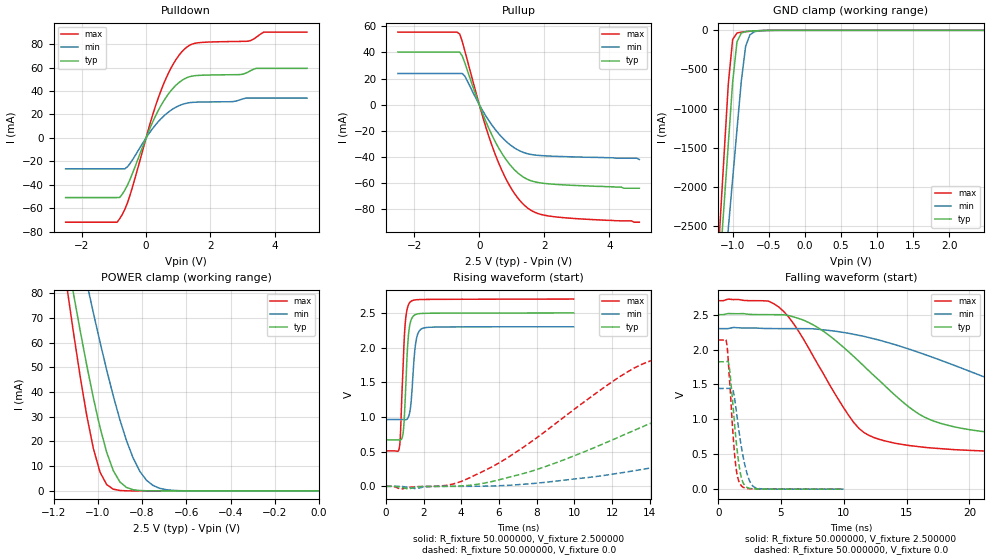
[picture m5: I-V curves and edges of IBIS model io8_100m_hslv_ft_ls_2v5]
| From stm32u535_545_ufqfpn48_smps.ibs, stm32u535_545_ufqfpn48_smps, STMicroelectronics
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|   Model io8_100m_hslv_ft_ls_2v5
[Model]  io8_100m_hslv_ft_ls_2v5
Model_type I/O
Polarity   Non-Inverting
Enable   Active-Low
Vinl =   0.750000V
Vinh =   1.750000V
Vmeas =  1.250000V
Cref =   50.000000pF
Rref =   100.000000M
Vref =   0.0V
C_comp   3.340800pF   3.338500pF   3.380300pF
[Temperature Range]   25.000000   0.140000k   -40.000000
[Pullup Reference]   2.500000V   2.300000V   2.700000V
[Pulldown Reference]   0.0V   0.0V   0.0V
[POWER Clamp Reference]   2.500000V   2.300000V   2.700000V
[GND Clamp Reference]   0.0V   0.0V   0.0V
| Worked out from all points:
|   slope of the pulldown table from 0 to 0.375 V, typ, clamps not added: 16.1 ohm
|   slope of the pullup table from 0 to 0.375 V, typ, clamps not added: 16.6 ohm
|   GND clamp passes 1 mA (typ) near -0.50 V on its own axis
|   POWER clamp passes 1 mA (typ) near -0.86 V on its own axis
|   rising waveform, R_fixture 50.000000, V_fixture 2.500000: 20-80 % time 198ps typ, 224ps min, 202ps max; typ from 0.67 V to 2.5 V
|   rising waveform, R_fixture 50.000000, V_fixture 0.0: 20-80 % time 9.99ns typ, 18.1ns min, 6.67ns max; typ from 0 V to 1.82 V
|   falling waveform, R_fixture 50.000000, V_fixture 2.500000: 20-80 % time 7.07ns typ, 14.1ns min, 4.42ns max; typ from 2.5 V to 0.67 V
|   falling waveform, R_fixture 50.000000, V_fixture 0.0: 20-80 % time 599ps typ, 783ps min, 496ps max; typ from 1.82 V to 0 V
[Pulldown]
|Voltage   I(typ)   I(min)   I(max)
-2.5V     -51mA      -26.45mA   -72.04mA
-900mV    -51mA      -26.45mA   -72.04mA
-820mV    -50.89mA   -26.45mA   -69.09mA
-500mV    -35.59mA   -21.93mA   -49.09mA
140mV     9.489mA    5.639mA    13.76mA
460mV     27.5mA     16.24mA    40.22mA
860mV     43.07mA    25.18mA    63.88mA
1.26V     51.38mA    29.65mA    77.49mA
1.66V     53.45mA    30.63mA    81.42mA
3.18V     56.44mA    34.01mA    82.68mA
3.66V     59.44mA    34.01mA    90.42mA
5V        59.44mA    34.01mA    90.42mA
[Pullup]
|Voltage   I(typ)   I(min)   I(max)
-2.5V     40.22mA    23.82mA    55.53mA
-680mV    40.22mA    23.82mA    55.53mA
-600mV    40.22mA    23.82mA    53.98mA
-440mV    31.7mA     21.6mA     40.82mA
120mV     -7.857mA   -5.279mA   -10.51mA
520mV     -29.75mA   -19.94mA   -40.02mA
760mV     -39.83mA   -26.61mA   -53.83mA
1V        -47.69mA   -31.74mA   -64.85mA
1.48V     -57.17mA   -37.55mA   -79.03mA
1.8V      -59.59mA   -38.81mA   -83.34mA
2.28V     -60.92mA   -39.5mA    -85.75mA
4.92V     -64mA      -42mA      -90mA
[GND_clamp]
|Voltage   I(typ)   I(min)   I(max)
-2.5V     -9.446A    -9.524A    -9.146A
-1.18V    -3.045A    -3.8A      -2.552A
-1.12V    -2.248A    -3.166A    -1.614A
-1.06V    -1.452A    -2.533A    -685.3mA
-1V       -665mA     -1.901A    -117.9mA
-940mV    -148mA     -1.272A    -34.32mA
-880mV    -35.13mA   -651.5mA   -22.79mA
-820mV    -16mA      -203.9mA   -17.07mA
-760mV    -10.46mA   -56.88mA   -12.26mA
-700mV    -7.068mA   -18.52mA   -8.146mA
-400mV    -103.3uA   -375.9uA   -42.12uA
2.48V     0A         14.84nA    0A
[POWER_clamp]
|Voltage   I(typ)   I(min)   I(max)
-2.49V    881mA      773.1mA    1.07A
-1.14V    95.25mA    122.7mA    82.82mA
-1.11V    79.9mA     109.7mA    64.14mA
-1.05V    50.87mA    84.26mA    30.57mA
-1.02V    37.63mA    72.04mA    17.17mA
-990mV    25.71mA    60.25mA    7.621mA
-930mV    8.217mA    38.43mA    713.9uA
-900mV    3.624mA    28.77mA    182.8uA
-840mV    490.7uA    13.24mA    11.35uA
-780mV    56.55uA    4.324mA    699nA
-660mV    716.5nA    226uA      9.775nA
0V        0A         19.49nA    0A
[Ramp]
| variable   typ   min   max
dV/dt_r  1.09512/9.97558n   0.86586/18.04086n   1.28196/6.65918n
dV/dt_f  1.09811/7.06277n   0.80210/14.07935n   1.31360/4.41676n
R_load = 50.000000
[Rising Waveform]
R_fixture= 50.000000
V_fixture= 2.500000
V_fixture_min= 2.300000
V_fixture_max= 2.700000
|time   V(typ)   V(min)   V(max)
0s        669.8mV    963.1mV    510.7mV
720.7ps   666.1mV    963.2mV    563.3mV
780.8ps   667.7mV    963mV      792.4mV
920.9ps   781.1mV    962mV      1.769V
1.021ns   1.226V     959.4mV    2.325V
1.161ns   2.048V     981.1mV    2.587V
1.321ns   2.383V     1.169V     2.665V
1.582ns   2.477V     2.06V      2.689V
1.922ns   2.493V     2.275V     2.694V
9.97ns    2.5V       2.3V       2.7V
[Rising Waveform]
R_fixture= 50.000000
V_fixture= 0.0
V_fixture_min= 0.0
V_fixture_max= 0.0
|time   V(typ)   V(min)   V(max)
0s        2.565nV    124.9nV    2.595nV
4.404ns   13.92mV    31.96uV    117.6mV
8.008ns   241.8mV    44.83mV    700mV
12.41ns   715.8mV    191.1mV    1.581V
14.41ns   950.8mV    281.3mV    1.844V
18.82ns   1.423V     502.4mV    2.036V
21.62ns   1.595V     650.2mV    2.082V
33.23ns   1.785V     1.173V     2.131V
50.05ns   1.821V     1.388V     2.136V
199.4ns   1.825V     1.443V     2.137V
[Falling Waveform]
R_fixture= 50.000000
V_fixture= 2.500000
V_fixture_min= 2.300000
V_fixture_max= 2.700000
|time   V(typ)   V(min)   V(max)
0s        2.5V       2.3V       2.7V
4.004ns   2.5V       2.301V     2.694V
5.205ns   2.499V     2.3V       2.548V
8.008ns   2.307V     2.29V      1.765V
11.61ns   1.762V     2.189V     810.5mV
15.62ns   1.12V      1.981V     616.4mV
18.82ns   892.1mV    1.772V     565.8mV
28.83ns   727.8mV    1.231V     521.6mV
49.65ns   676.3mV    1.017V     511.1mV
199.4ns   669.8mV    963.1mV    510.7mV
[Falling Waveform]
R_fixture= 50.000000
V_fixture= 0.0
V_fixture_min= 0.0
V_fixture_max= 0.0
|time   V(typ)   V(min)   V(max)
0s        1.825V     1.443V     2.137V
620.6ps   1.825V     1.443V     2.139V
840.8ps   1.797V     1.443V     1.73V
1.141ns   1.277V     1.439V     890.1mV
1.361ns   817.6mV    1.23V      397mV
1.562ns   478.6mV    955.9mV    163.3mV
1.822ns   181.8mV    630.1mV    53.65mV
2.362ns   20.4mV     185.8mV    7.811mV
2.943ns   3.775mV    22.57mV    3.133mV
9.97ns    2.565nV    124.9nV    2.595nV
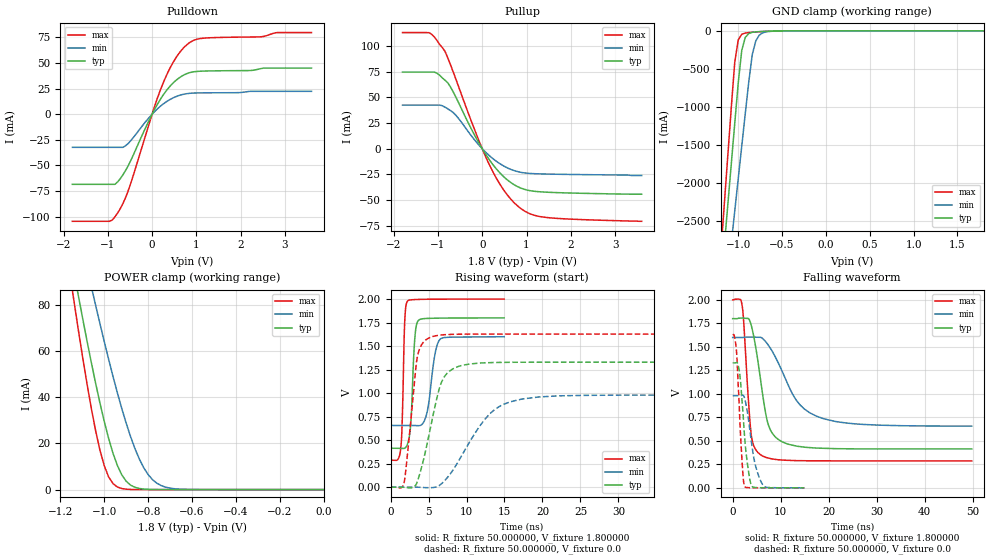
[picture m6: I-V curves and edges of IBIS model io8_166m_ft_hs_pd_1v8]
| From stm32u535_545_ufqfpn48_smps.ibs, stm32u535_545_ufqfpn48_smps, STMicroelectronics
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|   Model io8_166m_ft_hs_pd_1v8
[Model]  io8_166m_ft_hs_pd_1v8
Model_type I/O
Polarity   Non-Inverting
Enable   Active-Low
Vinl =   0.540000V
Vinh =   1.260000V
Vmeas =  0.900000V
Cref =   50.000000pF
Rref =   100.000000M
Vref =   0.0V
C_comp   3.358200pF   3.352700pF   3.400300pF
[Temperature Range]   25.000000   0.140000k   -40.000000
[Pullup Reference]   1.800000V   1.600000V   2.000000V
[Pulldown Reference]   0.0V   0.0V   0.0V
[POWER Clamp Reference]   1.800000V   1.600000V   2.000000V
[GND Clamp Reference]   0.0V   0.0V   0.0V
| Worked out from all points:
|   slope of the pulldown table from 0 to 0.27 V, typ, clamps not added: 13.6 ohm
|   slope of the pullup table from 0 to 0.27 V, typ, clamps not added: 15.9 ohm
|   GND clamp passes 1 mA (typ) near -0.50 V on its own axis
|   POWER clamp passes 1 mA (typ) near -0.86 V on its own axis
|   rising waveform, R_fixture 50.000000, V_fixture 1.800000: 20-80 % time 469ps typ, 917ps min, 313ps max; typ from 0.414 V to 1.8 V
|   rising waveform, R_fixture 50.000000, V_fixture 0.0: 20-80 % time 2.22ns typ, 4.8ns min, 1.18ns max; typ from 0 V to 1.33 V
|   falling waveform, R_fixture 50.000000, V_fixture 1.800000: 20-80 % time 2.61ns typ, 6.11ns min, 1.3ns max; typ from 1.8 V to 0.414 V
|   falling waveform, R_fixture 50.000000, V_fixture 0.0: 20-80 % time 1.31ns typ, 1.86ns min, 936ps max; typ from 1.33 V to 0 V
[Pulldown]
|Voltage   I(typ)   I(min)   I(max)
-1.8V     -68.38mA   -32.32mA   -104.4mA
-960mV    -68.38mA   -32.32mA   -104.4mA
-780mV    -66.08mA   -32.32mA   -96.43mA
-660mV    -59.2mA    -32.31mA   -87.22mA
-540mV    -50.22mA   -28.51mA   -74.66mA
0V        -10fA      -200fA     0A
240mV     18.04mA    9.6mA      29.42mA
480mV     30.68mA    16.02mA    50.95mA
780mV     39.48mA    19.99mA    67.56mA
1.14V     41.99mA    20.78mA    74.01mA
2.82V     44.93mA    22.28mA    79.57mA
3.6V      44.93mA    22.28mA    79.57mA
[Pullup]
|Voltage   I(typ)   I(min)   I(max)
-1.8V     74.48mA    42.39mA    112.9mA
-1.2V     74.48mA    42.39mA    112.8mA
-1.02V    73.37mA    42.39mA    105.2mA
-840mV    66.55mA    40.38mA    94.55mA
-600mV    50.53mA    32.71mA    68.14mA
-180mV    13.77mA    8.913mA    19.32mA
180mV     -11.9mA    -7.442mA   -17.26mA
480mV     -26.98mA   -16.65mA   -39.76mA
840mV     -37.65mA   -22.63mA   -57.07mA
1.08V     -40.74mA   -24.01mA   -63.22mA
1.44V     -42.19mA   -24.58mA   -66.73mA
3.6V      -44.2mA    -26mA      -70.5mA
[GND_clamp]
|Voltage   I(typ)   I(min)   I(max)
-1.8V     -9.908A    -9.683A    -9.994A
-1.2V     -3.383A    -4.084A    -2.934A
-1.16V    -2.841A    -3.655A    -2.294A
-1.12V    -2.299A    -3.226A    -1.656A
-1.04V    -1.218A    -2.369A    -414.2mA
-1V       -684.7mA   -1.941A    -119.2mA
-960mV    -257.2mA   -1.514A    -45.67mA
-920mV    -87.04mA   -1.089A    -28.94mA
-840mV    -19.36mA   -312.8mA   -18.98mA
-800mV    -13.56mA   -132.4mA   -15.51mA
-720mV    -8.053mA   -25.67mA   -9.505mA
1.8V      45.71uA    33.32uA    56.11uA
[POWER_clamp]
|Voltage   I(typ)   I(min)   I(max)
-1.8V     470.8mA    433.7mA    554.6mA
-1.14V    95.25mA    122.7mA    82.82mA
-1.12V    84.97mA    114mA      70.27mA
-1.06V    55.51mA    88.42mA    35.67mA
-1.04V    46.34mA    80.15mA    25.76mA
-1V       29.51mA    64.13mA    10.3mA
-940mV    10.39mA    41.86mA    1.109mA
-900mV    3.624mA    28.77mA    182.8uA
-840mV    490.7uA    13.24mA    11.35uA
-800mV    116.8uA    6.532mA    1.77uA
-740mV    13.2uA     1.724mA    109.3nA
0V        0A         18.75nA    0A
[Ramp]
| variable   typ   min   max
dV/dt_r  0.79740/2.21597n   0.58782/4.79180n   0.97632/1.17729n
dV/dt_f  0.83143/2.60081n   0.56562/6.09244n   1.02745/1.29981n
R_load = 50.000000
[Rising Waveform]
R_fixture= 50.000000
V_fixture= 1.800000
V_fixture_min= 1.600000
V_fixture_max= 2.000000
|time   V(typ)   V(min)   V(max)
0s        413.8mV    656.4mV    287.1mV
1.351ns   413.4mV    656.4mV    419.6mV
1.862ns   414.5mV    656.4mV    1.757V
2.192ns   451.1mV    656.4mV    1.974V
2.613ns   631.7mV    656.3mV    1.991V
3.153ns   1.54V      655.7mV    1.994V
3.604ns   1.766V     654.2mV    1.996V
4.805ns   1.794V     796mV      1.998V
6.577ns   1.797V     1.577V     1.999V
14.95ns   1.8V       1.599V     1.999V
[Rising Waveform]
R_fixture= 50.000000
V_fixture= 0.0
V_fixture_min= 0.0
V_fixture_max= 0.0
|time   V(typ)   V(min)   V(max)
0s        1.722uV    2.329uV    145nV
1.802ns   -1.128mV   20.47nV    55.07mV
3.504ns   56.19mV    15.53uV    1.376V
5.005ns   535.1mV    -5.355mV   1.585V
6.206ns   984.2mV    9.017mV    1.614V
6.907ns   1.15V      52.35mV    1.62V
9.61ns    1.298V     370mV      1.627V
13.31ns   1.325V     798.1mV    1.627V
17.32ns   1.328V     937.5mV    1.628V
49.85ns   1.329V     979.8mV    1.628V
[Falling Waveform]
R_fixture= 50.000000
V_fixture= 1.800000
V_fixture_min= 1.600000
V_fixture_max= 2.000000
|time   V(typ)   V(min)   V(max)
0s        1.8V       1.599V     1.999V
1.902ns   1.806V     1.599V     1.96V
2.302ns   1.806V     1.601V     1.766V
3.804ns   1.742V     1.604V     594.6mV
5.606ns   1.227V     1.601V     360.1mV
7.608ns   646.9mV    1.505V     314.8mV
11.61ns   463.9mV    1.089V     292.5mV
14.91ns   433.3mV    840.1mV    288.6mV
21.22ns   417.3mV    708.1mV    287.3mV
49.85ns   413.8mV    656.4mV    287.1mV
[Falling Waveform]
R_fixture= 50.000000
V_fixture= 0.0
V_fixture_min= 0.0
V_fixture_max= 0.0
|time   V(typ)   V(min)   V(max)
0s        1.329V     979.8mV    1.628V
720.7ps   1.331V     979.8mV    1.498V
1.381ns   1.243V     979.6mV    855.5mV
2.072ns   855.7mV    985.7mV    197.4mV
2.492ns   539.8mV    951.8mV    15.9mV
3.153ns   230.2mV    776.6mV    2.816mV
3.844ns   35.31mV    511.7mV    1.423mV
4.715ns   3.956mV    246.1mV    843uV
6.126ns   1.334mV    44.42mV    498.2uV
14.95ns   1.722uV    2.329uV    145nV
